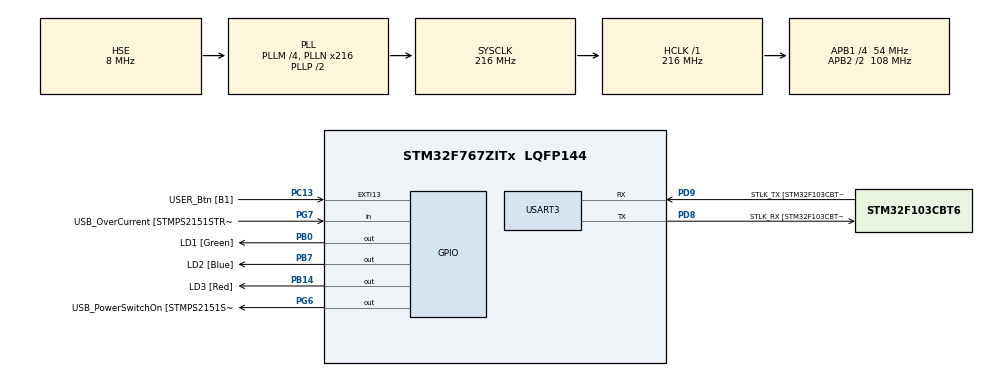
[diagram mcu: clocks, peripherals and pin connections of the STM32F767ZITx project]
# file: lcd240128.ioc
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CORTEX_M7.CPU_DCache=Enabled
CORTEX_M7.CPU_ICache=Enabled
Mcu.Family=STM32F7
Mcu.Name=STM32F767ZITx
Mcu.Package=LQFP144
NVIC.PriorityGroup=NVIC_PRIORITYGROUP_4
PA1.GPIO_Label=RMII_REF_CLK [LAN8742A-CZ-TR_REFCLK0]
PA1.Signal=ETH_REF_CLK
PA10.GPIO_Label=USB_ID
PA10.Signal=USB_OTG_FS_ID
PA11.GPIO_Label=USB_DM
PA11.Signal=USB_OTG_FS_DM
PA12.GPIO_Label=USB_DP
PA12.Signal=USB_OTG_FS_DP
PA13.GPIO_Label=TMS
PA13.Mode=Trace_Asynchronous_SW
PA13.Signal=SYS_JTMS-SWDIO
PA14.GPIO_Label=TCK
PA14.Mode=Trace_Asynchronous_SW
PA14.Signal=SYS_JTCK-SWCLK
PA2.GPIO_Label=RMII_MDIO [LAN8742A-CZ-TR_MDIO]
PA2.Signal=ETH_MDIO
PA7.GPIO_Label=RMII_CRS_DV [LAN8742A-CZ-TR_CRS_DV]
PA7.Signal=ETH_CRS_DV
PA8.GPIO_Label=USB_SOF [TP1]
PA8.Signal=USB_OTG_FS_SOF
PA9.GPIO_Label=USB_VBUS
PA9.Signal=USB_OTG_FS_VBUS
PB0.GPIO_Label=LD1 [Green]
PB0.Signal=GPIO_Output
PB13.GPIO_Label=RMII_TXD1 [LAN8742A-CZ-TR_TXD1]
PB13.Signal=ETH_TXD1
PB14.GPIO_Label=LD3 [Red]
PB14.Signal=GPIO_Output
PB3.GPIO_Label=SWO
PB3.Mode=Trace_Asynchronous_SW
PB3.Signal=SYS_JTDO-SWO
PB7.GPIO_Label=LD2 [Blue]
PB7.Signal=GPIO_Output
PC1.GPIO_Label=RMII_MDC [LAN8742A-CZ-TR_MDC]
PC1.Signal=ETH_MDC
PC13.GPIO_Label=USER_Btn [B1]
PC13.Signal=GPXTI13
PC14/OSC32_IN.Signal=RCC_OSC32_IN
PC15/OSC32_OUT.Signal=RCC_OSC32_OUT
PC4.GPIO_Label=RMII_RXD0 [LAN8742A-CZ-TR_RXD0]
PC4.Signal=ETH_RXD0
PC5.GPIO_Label=RMII_RXD1 [LAN8742A-CZ-TR_RXD1]
PC5.Signal=ETH_RXD1
PD8.GPIO_Label=STLK_RX [STM32F103CBT6_PA3]
PD8.Mode=Asynchronous
PD8.Signal=USART3_TX
PD9.GPIO_Label=STLK_TX [STM32F103CBT6_PA2]
PD9.Mode=Asynchronous
PD9.Signal=USART3_RX
PG11.GPIO_Label=RMII_TX_EN [LAN8742A-CZ-TR_TXEN]
PG11.Signal=ETH_TX_EN
PG13.GPIO_Label=RMII_TXD0 [LAN8742A-CZ-TR_TXD0]
PG13.Signal=ETH_TXD0
PG6.GPIO_Label=USB_PowerSwitchOn [STMPS2151STR_EN]
PG6.Signal=GPIO_Output
PG7.GPIO_Label=USB_OverCurrent [STMPS2151STR_FAULT]
PG7.Signal=GPIO_Input
PH0/OSC_IN.GPIO_Label=MCO [STM32F103CBT6_PA8]
PH0/OSC_IN.Mode=HSE-External-Clock-Source
PH0/OSC_IN.Signal=RCC_OSC_IN
PH1/OSC_OUT.Mode=HSE-External-Clock-Source
PH1/OSC_OUT.Signal=RCC_OSC_OUT
ProjectManager.HeapSize=0x200
ProjectManager.StackSize=0x400
ProjectManager.TargetToolchain=STM32CubeIDE
RCC.48MHZClocksFreq_Value=24000000
RCC.AHBFreq_Value=216000000
RCC.APB1CLKDivider=RCC_HCLK_DIV4
RCC.APB1Freq_Value=54000000
RCC.APB1TimFreq_Value=108000000
RCC.APB2CLKDivider=RCC_HCLK_DIV2
RCC.APB2Freq_Value=108000000
RCC.APB2TimFreq_Value=216000000
RCC.CortexFreq_Value=216000000
RCC.HCLKFreq_Value=216000000
RCC.HSE_VALUE=8000000
RCC.HSI_VALUE=16000000
RCC.LSE_VALUE=32768
RCC.PLLM=4
RCC.PLLMUL=RCC_PLL_MUL9
RCC.PLLN=216
RCC.PLLQ=4
RCC.PLLSourceVirtual=RCC_PLLSOURCE_HSE
RCC.PRESCALERUSB=RCC_USBCLKSOURCE_PLL_DIV1_5
RCC.SYSCLKFreq_VALUE=216000000
RCC.SYSCLKSource=RCC_SYSCLKSOURCE_PLLCLK
RCC.SYSCLKSourceVirtual=RCC_SYSCLKSOURCE_PLLCLK
RCC.USBFreq_Value=108000000
RCC.VCOOutputFreq_Value=432000000
USART3.Parity=PARITY_EVEN
USART3.VirtualMode-Asynchronous=VM_ASYNC
USART3.WordLength=WORDLENGTH_9B
VP_TIM11_VS_ClockSourceINT.Mode=Enable_Timer
board=NUCLEO-F767ZI

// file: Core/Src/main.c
/* USER CODE BEGIN Header */
/**
  ******************************************************************************
  * @file           : main.c
  * @brief          : Main program body
  ******************************************************************************
  * @attention
  *
  * Copyright (c) 2023 STMicroelectronics.
  * All rights reserved.
  *
  * This software is licensed under terms that can be found in the LICENSE file
  * in the root directory of this software component.
  * If no LICENSE file comes with this software, it is provided AS-IS.
  *
  ******************************************************************************
  */
/* USER CODE END Header */
#include "main.h"

/* USER CODE BEGIN Includes */
#include "stm32f7xx_ll_rcc.h"

#include "frt.h"
#include "ra6963.h"

/* USER CODE END Includes */

TIM_HandleTypeDef htim11;

UART_HandleTypeDef huart3;

void SystemClock_Config(void);
static void MX_GPIO_Init(void);
static void MX_USART3_UART_Init(void);
static void MX_TIM11_Init(void);

/* USER CODE BEGIN 0 */
volatile uint16_t delay=65000;
/* USER CODE END 0 */

int main(void)
{

  /* Enable I-Cache---------------------------------------------------------*/
  SCB_EnableICache();

  /* Enable D-Cache---------------------------------------------------------*/
  SCB_EnableDCache();

  /* MCU Configuration--------------------------------------------------------*/

  /* Reset of all peripherals, Initializes the Flash interface and the Systick. */
  HAL_Init();

  /* Configure the system clock */
  SystemClock_Config();

  /* USER CODE BEGIN SysInit */
  //LL_RCC_SetTIMPrescaler(LL_RCC_TIM_PRESCALER_FOUR_TIMES);

  /* USER CODE END SysInit */

  /* Initialize all configured peripherals */
  MX_GPIO_Init();
  MX_USART3_UART_Init();
  MX_TIM11_Init();

  /* Infinite loop */
  /* USER CODE BEGIN WHILE */
  uint32_t c=0;

  lcd_init();

  while (1)
  {
    /* USER CODE END WHILE */

    /* USER CODE BEGIN 3 */
	  //if(c&1)HAL_GPIO_TogglePin(LD1_GPIO_Port,LD1_Pin);
	  if(c&2)HAL_GPIO_TogglePin(LD2_GPIO_Port,LD2_Pin);
	  if(c&4)HAL_GPIO_TogglePin(LD3_GPIO_Port,LD3_Pin);

	  //HAL_Delay(100);
	  //frt_wait_ns3(delay);
	  LD1_GPIO_Port->BSRR = LD1_Pin;
	  frt_wait_nops(delay);
//	  lcd_set_data(c);
	  delay= lcd_get_data();
	  LD1_GPIO_Port->BSRR = LD1_Pin<<16;
	  c++;
  }
  /* USER CODE END 3 */
}

void SystemClock_Config(void)
{
  RCC_OscInitTypeDef RCC_OscInitStruct = {0};
  RCC_ClkInitTypeDef RCC_ClkInitStruct = {0};

  /** Configure the main internal regulator output voltage
  */
  __HAL_RCC_PWR_CLK_ENABLE();
  __HAL_PWR_VOLTAGESCALING_CONFIG(PWR_REGULATOR_VOLTAGE_SCALE1);

  /** Initializes the RCC Oscillators according to the specified parameters
  * in the RCC_OscInitTypeDef structure.
  */
  RCC_OscInitStruct.OscillatorType = RCC_OSCILLATORTYPE_HSE;
  RCC_OscInitStruct.HSEState = RCC_HSE_BYPASS;
  RCC_OscInitStruct.PLL.PLLState = RCC_PLL_ON;
  RCC_OscInitStruct.PLL.PLLSource = RCC_PLLSOURCE_HSE;
  RCC_OscInitStruct.PLL.PLLM = 4;
  RCC_OscInitStruct.PLL.PLLN = 216;
  RCC_OscInitStruct.PLL.PLLP = RCC_PLLP_DIV2;
  RCC_OscInitStruct.PLL.PLLQ = 4;
  RCC_OscInitStruct.PLL.PLLR = 2;
  if (HAL_RCC_OscConfig(&RCC_OscInitStruct) != HAL_OK)
  {
    Error_Handler();
  }

  /** Activate the Over-Drive mode
  */
  if (HAL_PWREx_EnableOverDrive() != HAL_OK)
  {
    Error_Handler();
  }

  /** Initializes the CPU, AHB and APB buses clocks
  */
  RCC_ClkInitStruct.ClockType = RCC_CLOCKTYPE_HCLK|RCC_CLOCKTYPE_SYSCLK
                              |RCC_CLOCKTYPE_PCLK1|RCC_CLOCKTYPE_PCLK2;
  RCC_ClkInitStruct.SYSCLKSource = RCC_SYSCLKSOURCE_PLLCLK;
  RCC_ClkInitStruct.AHBCLKDivider = RCC_SYSCLK_DIV1;
  RCC_ClkInitStruct.APB1CLKDivider = RCC_HCLK_DIV4;
  RCC_ClkInitStruct.APB2CLKDivider = RCC_HCLK_DIV2;

  if (HAL_RCC_ClockConfig(&RCC_ClkInitStruct, FLASH_LATENCY_7) != HAL_OK)
  {
    Error_Handler();
  }
}

static void MX_TIM11_Init(void)
{

  htim11.Instance = TIM11;
  htim11.Init.Prescaler = 0;
  htim11.Init.CounterMode = TIM_COUNTERMODE_UP;
  htim11.Init.Period = 65535;
  htim11.Init.ClockDivision = TIM_CLOCKDIVISION_DIV1;
  htim11.Init.AutoReloadPreload = TIM_AUTORELOAD_PRELOAD_DISABLE;
  if (HAL_TIM_Base_Init(&htim11) != HAL_OK)
  {
    Error_Handler();
  }

}

static void MX_USART3_UART_Init(void)
{

  huart3.Instance = USART3;
  huart3.Init.BaudRate = 115200;
  huart3.Init.WordLength = UART_WORDLENGTH_9B;
  huart3.Init.StopBits = UART_STOPBITS_1;
  huart3.Init.Parity = UART_PARITY_EVEN;
  huart3.Init.Mode = UART_MODE_TX_RX;
  huart3.Init.HwFlowCtl = UART_HWCONTROL_NONE;
  huart3.Init.OverSampling = UART_OVERSAMPLING_16;
  huart3.Init.OneBitSampling = UART_ONE_BIT_SAMPLE_DISABLE;
  huart3.AdvancedInit.AdvFeatureInit = UART_ADVFEATURE_NO_INIT;
  if (HAL_UART_Init(&huart3) != HAL_OK)
  {
    Error_Handler();
  }

}

static void MX_GPIO_Init(void)
{
  GPIO_InitTypeDef GPIO_InitStruct = {0};

  /* GPIO Ports Clock Enable */
  __HAL_RCC_GPIOE_CLK_ENABLE();
  __HAL_RCC_GPIOC_CLK_ENABLE();
  __HAL_RCC_GPIOH_CLK_ENABLE();
  __HAL_RCC_GPIOA_CLK_ENABLE();
  __HAL_RCC_GPIOB_CLK_ENABLE();
  __HAL_RCC_GPIOD_CLK_ENABLE();
  __HAL_RCC_GPIOG_CLK_ENABLE();

  /*Configure GPIO pin Output Level */
  HAL_GPIO_WritePin(lcd_wr_GPIO_Port, lcd_wr_Pin, GPIO_PIN_SET);

  /*Configure GPIO pin Output Level */
  HAL_GPIO_WritePin(GPIOB, LD1_Pin|LD3_Pin|LD2_Pin, GPIO_PIN_RESET);

  /*Configure GPIO pin Output Level */
  HAL_GPIO_WritePin(GPIOG, lcd_d2_Pin|lcd_d1_Pin|USB_PowerSwitchOn_Pin, GPIO_PIN_RESET);

  /*Configure GPIO pin Output Level */
  HAL_GPIO_WritePin(GPIOC, lcd_fs_Pin|lcd_d7_Pin|lcd_d6_Pin|lcd_d5_Pin
                          |lcd_d4_Pin, GPIO_PIN_RESET);

  /*Configure GPIO pin Output Level */
  HAL_GPIO_WritePin(GPIOD, lcd_d3_Pin|lcd_cd_Pin|lcd_rst_Pin|lcd_d0_Pin, GPIO_PIN_RESET);

  /*Configure GPIO pin Output Level */
  HAL_GPIO_WritePin(GPIOD, lcd_rd_Pin|lcd_ce_Pin, GPIO_PIN_SET);

  /*Configure GPIO pin : lcd_wr_Pin */
  GPIO_InitStruct.Pin = lcd_wr_Pin;
  GPIO_InitStruct.Mode = GPIO_MODE_OUTPUT_PP;
  GPIO_InitStruct.Pull = GPIO_NOPULL;
  GPIO_InitStruct.Speed = GPIO_SPEED_FREQ_MEDIUM;
  HAL_GPIO_Init(lcd_wr_GPIO_Port, &GPIO_InitStruct);

  /*Configure GPIO pin : USER_Btn_Pin */
  GPIO_InitStruct.Pin = USER_Btn_Pin;
  GPIO_InitStruct.Mode = GPIO_MODE_IT_RISING;
  GPIO_InitStruct.Pull = GPIO_NOPULL;
  HAL_GPIO_Init(USER_Btn_GPIO_Port, &GPIO_InitStruct);

  /*Configure GPIO pins : RMII_MDC_Pin RMII_RXD0_Pin RMII_RXD1_Pin */
  GPIO_InitStruct.Pin = RMII_MDC_Pin|RMII_RXD0_Pin|RMII_RXD1_Pin;
  GPIO_InitStruct.Mode = GPIO_MODE_AF_PP;
  GPIO_InitStruct.Pull = GPIO_NOPULL;
  GPIO_InitStruct.Speed = GPIO_SPEED_FREQ_VERY_HIGH;
  GPIO_InitStruct.Alternate = GPIO_AF11_ETH;
  HAL_GPIO_Init(GPIOC, &GPIO_InitStruct);

  /*Configure GPIO pins : RMII_REF_CLK_Pin RMII_MDIO_Pin RMII_CRS_DV_Pin */
  GPIO_InitStruct.Pin = RMII_REF_CLK_Pin|RMII_MDIO_Pin|RMII_CRS_DV_Pin;
  GPIO_InitStruct.Mode = GPIO_MODE_AF_PP;
  GPIO_InitStruct.Pull = GPIO_NOPULL;
  GPIO_InitStruct.Speed = GPIO_SPEED_FREQ_VERY_HIGH;
  GPIO_InitStruct.Alternate = GPIO_AF11_ETH;
  HAL_GPIO_Init(GPIOA, &GPIO_InitStruct);

  /*Configure GPIO pins : LD1_Pin LD3_Pin LD2_Pin */
  GPIO_InitStruct.Pin = LD1_Pin|LD3_Pin|LD2_Pin;
  GPIO_InitStruct.Mode = GPIO_MODE_OUTPUT_PP;
  GPIO_InitStruct.Pull = GPIO_NOPULL;
  GPIO_InitStruct.Speed = GPIO_SPEED_FREQ_LOW;
  HAL_GPIO_Init(GPIOB, &GPIO_InitStruct);

  /*Configure GPIO pin : RMII_TXD1_Pin */
  GPIO_InitStruct.Pin = RMII_TXD1_Pin;
  GPIO_InitStruct.Mode = GPIO_MODE_AF_PP;
  GPIO_InitStruct.Pull = GPIO_NOPULL;
  GPIO_InitStruct.Speed = GPIO_SPEED_FREQ_VERY_HIGH;
  GPIO_InitStruct.Alternate = GPIO_AF11_ETH;
  HAL_GPIO_Init(RMII_TXD1_GPIO_Port, &GPIO_InitStruct);

  /*Configure GPIO pins : lcd_d2_Pin lcd_d1_Pin */
  GPIO_InitStruct.Pin = lcd_d2_Pin|lcd_d1_Pin;
  GPIO_InitStruct.Mode = GPIO_MODE_OUTPUT_PP;
  GPIO_InitStruct.Pull = GPIO_NOPULL;
  GPIO_InitStruct.Speed = GPIO_SPEED_FREQ_MEDIUM;
  HAL_GPIO_Init(GPIOG, &GPIO_InitStruct);

  /*Configure GPIO pin : USB_PowerSwitchOn_Pin */
  GPIO_InitStruct.Pin = USB_PowerSwitchOn_Pin;
  GPIO_InitStruct.Mode = GPIO_MODE_OUTPUT_PP;
  GPIO_InitStruct.Pull = GPIO_NOPULL;
  GPIO_InitStruct.Speed = GPIO_SPEED_FREQ_LOW;
  HAL_GPIO_Init(USB_PowerSwitchOn_GPIO_Port, &GPIO_InitStruct);

  /*Configure GPIO pin : USB_OverCurrent_Pin */
  GPIO_InitStruct.Pin = USB_OverCurrent_Pin;
  GPIO_InitStruct.Mode = GPIO_MODE_INPUT;
  GPIO_InitStruct.Pull = GPIO_NOPULL;
  HAL_GPIO_Init(USB_OverCurrent_GPIO_Port, &GPIO_InitStruct);

  /*Configure GPIO pins : lcd_fs_Pin lcd_d7_Pin lcd_d6_Pin lcd_d5_Pin
                           lcd_d4_Pin */
  GPIO_InitStruct.Pin = lcd_fs_Pin|lcd_d7_Pin|lcd_d6_Pin|lcd_d5_Pin
                          |lcd_d4_Pin;
  GPIO_InitStruct.Mode = GPIO_MODE_OUTPUT_PP;
  GPIO_InitStruct.Pull = GPIO_NOPULL;
  GPIO_InitStruct.Speed = GPIO_SPEED_FREQ_MEDIUM;
  HAL_GPIO_Init(GPIOC, &GPIO_InitStruct);

  /*Configure GPIO pins : USB_SOF_Pin USB_ID_Pin USB_DM_Pin USB_DP_Pin */
  GPIO_InitStruct.Pin = USB_SOF_Pin|USB_ID_Pin|USB_DM_Pin|USB_DP_Pin;
  GPIO_InitStruct.Mode = GPIO_MODE_AF_PP;
  GPIO_InitStruct.Pull = GPIO_NOPULL;
  GPIO_InitStruct.Speed = GPIO_SPEED_FREQ_VERY_HIGH;
  GPIO_InitStruct.Alternate = GPIO_AF10_OTG_FS;
  HAL_GPIO_Init(GPIOA, &GPIO_InitStruct);

  /*Configure GPIO pin : USB_VBUS_Pin */
  GPIO_InitStruct.Pin = USB_VBUS_Pin;
  GPIO_InitStruct.Mode = GPIO_MODE_INPUT;
  GPIO_InitStruct.Pull = GPIO_NOPULL;
  HAL_GPIO_Init(USB_VBUS_GPIO_Port, &GPIO_InitStruct);

  /*Configure GPIO pins : lcd_d3_Pin lcd_rd_Pin lcd_ce_Pin lcd_cd_Pin
                           lcd_rst_Pin lcd_d0_Pin */
  GPIO_InitStruct.Pin = lcd_d3_Pin|lcd_rd_Pin|lcd_ce_Pin|lcd_cd_Pin
                          |lcd_rst_Pin|lcd_d0_Pin;
  GPIO_InitStruct.Mode = GPIO_MODE_OUTPUT_PP;
  GPIO_InitStruct.Pull = GPIO_NOPULL;
  GPIO_InitStruct.Speed = GPIO_SPEED_FREQ_MEDIUM;
  HAL_GPIO_Init(GPIOD, &GPIO_InitStruct);

  /*Configure GPIO pins : RMII_TX_EN_Pin RMII_TXD0_Pin */
  GPIO_InitStruct.Pin = RMII_TX_EN_Pin|RMII_TXD0_Pin;
  GPIO_InitStruct.Mode = GPIO_MODE_AF_PP;
  GPIO_InitStruct.Pull = GPIO_NOPULL;
  GPIO_InitStruct.Speed = GPIO_SPEED_FREQ_VERY_HIGH;
  GPIO_InitStruct.Alternate = GPIO_AF11_ETH;
  HAL_GPIO_Init(GPIOG, &GPIO_InitStruct);

}

void Error_Handler(void)
{
  __disable_irq();
  while (1)
  {
  }
}
